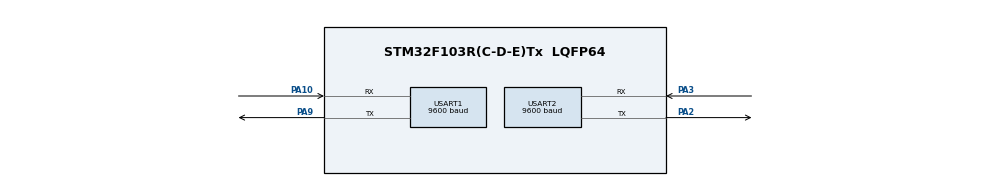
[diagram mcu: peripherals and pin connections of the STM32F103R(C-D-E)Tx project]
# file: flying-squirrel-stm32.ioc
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FREERTOS.Tasks01=defaultTask,24,128,StartDefaultTask,Default,NULL,Dynamic,NULL,NULL
Mcu.Family=STM32F1
Mcu.Name=STM32F103R(C-D-E)Tx
Mcu.Package=LQFP64
NVIC.PriorityGroup=NVIC_PRIORITYGROUP_4
NVIC.TIM1_UP_IRQn=true\:15\:0\:false\:false\:true\:false\:false\:true\:true
NVIC.TimeBase=TIM1_UP_IRQn
NVIC.TimeBaseIP=TIM1
NVIC.USART2_IRQn=true\:5\:0\:false\:false\:true\:true\:true\:true\:true
PA10.Mode=Asynchronous
PA10.Signal=USART1_RX
PA13.Mode=Serial_Wire
PA13.Signal=SYS_JTMS-SWDIO
PA14.Mode=Serial_Wire
PA14.Signal=SYS_JTCK-SWCLK
PA2.Mode=Asynchronous
PA2.Signal=USART2_TX
PA3.Mode=Asynchronous
PA3.Signal=USART2_RX
PA9.Mode=Asynchronous
PA9.Signal=USART1_TX
PD0-OSC_IN.Mode=HSE-External-Oscillator
PD0-OSC_IN.Signal=RCC_OSC_IN
PD1-OSC_OUT.Mode=HSE-External-Oscillator
PD1-OSC_OUT.Signal=RCC_OSC_OUT
ProjectManager.HeapSize=0x200
ProjectManager.StackSize=0x400
ProjectManager.TargetToolchain=CMake
RCC.APB1Freq_Value=8000000
RCC.APB2Freq_Value=8000000
RCC.SYSCLKSource=RCC_SYSCLKSOURCE_PLLCLK
USART1.BaudRate=9600
USART1.VirtualMode=VM_ASYNC
USART2.BaudRate=9600
USART2.VirtualMode=VM_ASYNC
VP_FREERTOS_VS_CMSIS_V2.Mode=CMSIS_V2
VP_SYS_VS_tim1.Mode=TIM1
board=custom

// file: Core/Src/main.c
/* USER CODE BEGIN Header */
/**
  ******************************************************************************
  * @file           : main.c
  * @brief          : Main program body
  ******************************************************************************
  * @attention
  *
  * Copyright (c) 2024 STMicroelectronics.
  * All rights reserved.
  *
  * This software is licensed under terms that can be found in the LICENSE file
  * in the root directory of this software component.
  * If no LICENSE file comes with this software, it is provided AS-IS.
  *
  ******************************************************************************
  */
/* USER CODE END Header */
#include "main.h"
#include "cmsis_os.h"
#include "usart.h"
#include "gpio.h"

void SystemClock_Config(void);
void MX_FREERTOS_Init(void);

int main(void)
{

  /* MCU Configuration--------------------------------------------------------*/

  /* Reset of all peripherals, Initializes the Flash interface and the Systick. */
  HAL_Init();

  /* Configure the system clock */
  SystemClock_Config();

  /* Initialize all configured peripherals */
  MX_GPIO_Init();
  MX_USART1_UART_Init();
  MX_USART2_UART_Init();
  /* Init scheduler */
  osKernelInitialize();

  /* Call init function for freertos objects (in cmsis_os2.c) */
  MX_FREERTOS_Init();

  /* Start scheduler */
  osKernelStart();

  /* We should never get here as control is now taken by the scheduler */

  /* Infinite loop */
  while (1)
  {

  }
}

void SystemClock_Config(void)
{
  RCC_OscInitTypeDef RCC_OscInitStruct = {0};
  RCC_ClkInitTypeDef RCC_ClkInitStruct = {0};

  /** Initializes the RCC Oscillators according to the specified parameters
  * in the RCC_OscInitTypeDef structure.
  */
  RCC_OscInitStruct.OscillatorType = RCC_OSCILLATORTYPE_HSI;
  RCC_OscInitStruct.HSIState = RCC_HSI_ON;
  RCC_OscInitStruct.HSICalibrationValue = RCC_HSICALIBRATION_DEFAULT;
  RCC_OscInitStruct.PLL.PLLState = RCC_PLL_NONE;
  if (HAL_RCC_OscConfig(&RCC_OscInitStruct) != HAL_OK)
  {
    Error_Handler();
  }

  /** Initializes the CPU, AHB and APB buses clocks
  */
  RCC_ClkInitStruct.ClockType = RCC_CLOCKTYPE_HCLK|RCC_CLOCKTYPE_SYSCLK
                              |RCC_CLOCKTYPE_PCLK1|RCC_CLOCKTYPE_PCLK2;
  RCC_ClkInitStruct.SYSCLKSource = RCC_SYSCLKSOURCE_HSI;
  RCC_ClkInitStruct.AHBCLKDivider = RCC_SYSCLK_DIV1;
  RCC_ClkInitStruct.APB1CLKDivider = RCC_HCLK_DIV1;
  RCC_ClkInitStruct.APB2CLKDivider = RCC_HCLK_DIV1;

  if (HAL_RCC_ClockConfig(&RCC_ClkInitStruct, FLASH_LATENCY_0) != HAL_OK)
  {
    Error_Handler();
  }
}

void HAL_TIM_PeriodElapsedCallback(TIM_HandleTypeDef *htim)
{
  if (htim->Instance == TIM6) {
    HAL_IncTick();
  }
}

void Error_Handler(void)
{
  __disable_irq();
  while (1)
  {
  }
}

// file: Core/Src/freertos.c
/* USER CODE BEGIN Header */
/**
  ******************************************************************************
  * File Name          : freertos.c
  * Description        : Code for freertos applications
  ******************************************************************************
  * @attention
  *
  * Copyright (c) 2024 STMicroelectronics.
  * All rights reserved.
  *
  * This software is licensed under terms that can be found in the LICENSE file
  * in the root directory of this software component.
  * If no LICENSE file comes with this software, it is provided AS-IS.
  *
  ******************************************************************************
  */
/* USER CODE END Header */

#include "FreeRTOS.h"
#include "task.h"
#include "main.h"
#include "cmsis_os.h"
/* USER CODE BEGIN Includes */
#include "shell_port.h"
#include "shell.h"
#include "elog.h"
/* USER CODE END Includes */

/* USER CODE BEGIN Variables */
static char *TAG = "main";
/* USER CODE END Variables */
/* Definitions for defaultTask */
osThreadId_t defaultTaskHandle;
const osThreadAttr_t defaultTask_attributes = {
  .name = "defaultTask",
  .stack_size = 128 * 4,
  .priority = (osPriority_t) osPriorityNormal,
};

void StartDefaultTask(void *argument);

void MX_FREERTOS_Init(void); /* (MISRA C 2004 rule 8.1) */

void MX_FREERTOS_Init(void) {

  /* Create the thread(s) */
  /* creation of defaultTask */
  defaultTaskHandle = osThreadNew(StartDefaultTask, NULL, &defaultTask_attributes);

}

void StartDefaultTask(void *argument)
{
  /* USER CODE BEGIN StartDefaultTask */
  UNUSED(argument);
  /* Infinite loop */
  easylogger_init();
  ShellInit();
  elog_i(TAG, "flying squirrel's default task start.");
  for(;;)
  {
    osDelay(1);
  }
  /* USER CODE END StartDefaultTask */
}
